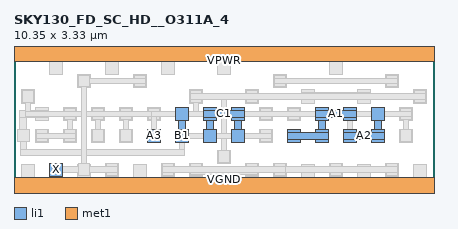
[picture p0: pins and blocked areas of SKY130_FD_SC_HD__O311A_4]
MACRO SKY130_FD_SC_HD__O311A_4
 CLASS CORE ;
 FOREIGN SKY130_FD_SC_HD__O311A_4 0 0 ;
 SIZE 10.35 BY 3.33 ;
 ORIGIN 0 0 ;
 SYMMETRY X Y R90 ;
 SITE unit ;
  PIN VPWR
   DIRECTION INOUT ;
   USE POWER ;
   SHAPE ABUTMENT ;
    PORT
     CLASS CORE ;
       LAYER li1 ;
        RECT 0.00000000 3.09000000 10.35000000 3.57000000 ;
       LAYER met1 ;
        RECT 0.00000000 3.09000000 10.35000000 3.57000000 ;
    END
  END VPWR

  PIN VGND
   DIRECTION INOUT ;
   USE POWER ;
   SHAPE ABUTMENT ;
    PORT
     CLASS CORE ;
       LAYER li1 ;
        RECT 0.00000000 -0.24000000 10.35000000 0.24000000 ;
       LAYER met1 ;
        RECT 0.00000000 -0.24000000 10.35000000 0.24000000 ;
    END
  END VGND

  PIN X
   DIRECTION INOUT ;
   USE SIGNAL ;
   SHAPE ABUTMENT ;
    PORT
     CLASS CORE ;
       LAYER li1 ;
        RECT 0.87000000 0.26000000 1.20000000 0.59000000 ;
    END
  END X

  PIN B1
   DIRECTION INOUT ;
   USE SIGNAL ;
   SHAPE ABUTMENT ;
    PORT
     CLASS CORE ;
       LAYER li1 ;
        RECT 3.97500000 1.09500000 4.30500000 1.42500000 ;
        RECT 4.05500000 1.42500000 4.22500000 1.63500000 ;
        RECT 3.97500000 1.63500000 4.30500000 1.96500000 ;
    END
  END B1

  PIN A3
   DIRECTION INOUT ;
   USE SIGNAL ;
   SHAPE ABUTMENT ;
    PORT
     CLASS CORE ;
       LAYER li1 ;
        RECT 3.28500000 1.09500000 3.61500000 1.42500000 ;
    END
  END A3

  PIN A1
   DIRECTION INOUT ;
   USE SIGNAL ;
   SHAPE ABUTMENT ;
    PORT
     CLASS CORE ;
       LAYER li1 ;
        RECT 6.73500000 1.09500000 7.06500000 1.17500000 ;
        RECT 7.42500000 1.09500000 7.75500000 1.17500000 ;
        RECT 6.73500000 1.17500000 7.75500000 1.34500000 ;
        RECT 6.73500000 1.34500000 7.06500000 1.42500000 ;
        RECT 7.42500000 1.34500000 7.75500000 1.42500000 ;
        RECT 7.50500000 1.42500000 7.67500000 1.63500000 ;
        RECT 7.42500000 1.63500000 7.75500000 1.71500000 ;
        RECT 8.11500000 1.63500000 8.44500000 1.71500000 ;
        RECT 7.42500000 1.71500000 8.44500000 1.88500000 ;
        RECT 7.42500000 1.88500000 7.75500000 1.96500000 ;
        RECT 8.11500000 1.88500000 8.44500000 1.96500000 ;
    END
  END A1

  PIN A2
   DIRECTION INOUT ;
   USE SIGNAL ;
   SHAPE ABUTMENT ;
    PORT
     CLASS CORE ;
       LAYER li1 ;
        RECT 8.11500000 1.09500000 8.44500000 1.17500000 ;
        RECT 8.80500000 1.09500000 9.13500000 1.17500000 ;
        RECT 8.11500000 1.17500000 9.13500000 1.34500000 ;
        RECT 8.11500000 1.34500000 8.44500000 1.42500000 ;
        RECT 8.80500000 1.34500000 9.13500000 1.42500000 ;
        RECT 8.88500000 1.42500000 9.05500000 1.63500000 ;
        RECT 8.80500000 1.63500000 9.13500000 1.96500000 ;
    END
  END A2

  PIN C1
   DIRECTION INOUT ;
   USE SIGNAL ;
   SHAPE ABUTMENT ;
    PORT
     CLASS CORE ;
       LAYER li1 ;
        RECT 4.66500000 1.09500000 4.99500000 1.42500000 ;
        RECT 5.35500000 1.09500000 5.68500000 1.42500000 ;
        RECT 4.74500000 1.42500000 4.91500000 1.63500000 ;
        RECT 5.43500000 1.42500000 5.60500000 1.63500000 ;
        RECT 4.66500000 1.63500000 4.99500000 1.71500000 ;
        RECT 5.35500000 1.63500000 5.68500000 1.71500000 ;
        RECT 4.66500000 1.71500000 5.68500000 1.88500000 ;
        RECT 4.66500000 1.88500000 4.99500000 1.96500000 ;
        RECT 5.35500000 1.88500000 5.68500000 1.96500000 ;
    END
  END C1

 OBS
    LAYER polycont ;
     RECT 0.60500000 1.17500000 0.77500000 1.34500000 ;
     RECT 1.29500000 1.17500000 1.46500000 1.34500000 ;
     RECT 1.98500000 1.17500000 2.15500000 1.34500000 ;
     RECT 2.67500000 1.17500000 2.84500000 1.34500000 ;
     RECT 1.29500000 1.71500000 1.46500000 1.88500000 ;
     RECT 1.98500000 1.71500000 2.15500000 1.88500000 ;
     RECT 2.67500000 1.71500000 2.84500000 1.88500000 ;
     RECT 3.36500000 1.71500000 3.53500000 1.88500000 ;
     RECT 8.19500000 1.17500000 8.36500000 1.34500000 ;
     RECT 8.88500000 1.17500000 9.05500000 1.34500000 ;
     RECT 6.81500000 1.71500000 6.98500000 1.88500000 ;
     RECT 8.88500000 1.71500000 9.05500000 1.88500000 ;
     RECT 6.81500000 1.17500000 6.98500000 1.34500000 ;
     RECT 7.50500000 1.17500000 7.67500000 1.34500000 ;
     RECT 7.50500000 1.71500000 7.67500000 1.88500000 ;
     RECT 8.19500000 1.71500000 8.36500000 1.88500000 ;
     RECT 3.36500000 1.17500000 3.53500000 1.34500000 ;
     RECT 9.57500000 1.17500000 9.74500000 1.34500000 ;
     RECT 6.12500000 1.71500000 6.29500000 1.88500000 ;
     RECT 9.57500000 1.71500000 9.74500000 1.88500000 ;
     RECT 4.74500000 1.17500000 4.91500000 1.34500000 ;
     RECT 5.43500000 1.17500000 5.60500000 1.34500000 ;
     RECT 4.74500000 1.71500000 4.91500000 1.88500000 ;
     RECT 5.43500000 1.71500000 5.60500000 1.88500000 ;
     RECT 4.05500000 1.17500000 4.22500000 1.34500000 ;
     RECT 6.12500000 1.17500000 6.29500000 1.34500000 ;
     RECT 0.60500000 1.71500000 0.77500000 1.88500000 ;
     RECT 4.05500000 1.71500000 4.22500000 1.88500000 ;

    LAYER pdiffc ;
     RECT 0.26000000 2.15000000 0.43000000 2.32000000 ;
     RECT 4.40000000 2.15000000 4.57000000 2.32000000 ;
     RECT 5.78000000 2.15000000 5.95000000 2.32000000 ;
     RECT 9.92000000 2.15000000 10.09000000 2.32000000 ;
     RECT 0.95000000 2.86000000 1.12000000 3.03000000 ;
     RECT 2.33000000 2.86000000 2.50000000 3.03000000 ;
     RECT 3.71000000 2.86000000 3.88000000 3.03000000 ;
     RECT 5.09000000 2.86000000 5.26000000 3.03000000 ;
     RECT 7.85000000 2.86000000 8.02000000 3.03000000 ;
     RECT 7.16000000 2.15000000 7.33000000 2.32000000 ;
     RECT 8.54000000 2.15000000 8.71000000 2.32000000 ;
     RECT 1.64000000 2.52500000 1.81000000 2.69500000 ;
     RECT 3.02000000 2.52500000 3.19000000 2.69500000 ;
     RECT 6.47000000 2.52500000 6.64000000 2.69500000 ;
     RECT 9.23000000 2.52500000 9.40000000 2.69500000 ;

    LAYER ndiffc ;
     RECT 5.09000000 0.66000000 5.26000000 0.83000000 ;
     RECT 4.40000000 0.34000000 4.57000000 0.51000000 ;
     RECT 5.78000000 0.34000000 5.95000000 0.51000000 ;
     RECT 3.71000000 0.34000000 3.88000000 0.51000000 ;
     RECT 6.47000000 0.34000000 6.64000000 0.51000000 ;
     RECT 7.85000000 0.34000000 8.02000000 0.51000000 ;
     RECT 9.23000000 0.34000000 9.40000000 0.51000000 ;
     RECT 0.26000000 0.30000000 0.43000000 0.47000000 ;
     RECT 1.64000000 0.30000000 1.81000000 0.47000000 ;
     RECT 3.02000000 0.30000000 3.19000000 0.47000000 ;
     RECT 7.16000000 0.30000000 7.33000000 0.47000000 ;
     RECT 8.54000000 0.30000000 8.71000000 0.47000000 ;
     RECT 9.92000000 0.30000000 10.09000000 0.47000000 ;
     RECT 0.95000000 0.34000000 1.12000000 0.51000000 ;
     RECT 2.33000000 0.34000000 2.50000000 0.51000000 ;

    LAYER li1 ;
     RECT 5.01000000 0.58000000 5.34000000 0.91000000 ;
     RECT 0.52500000 1.09500000 0.85500000 1.42500000 ;
     RECT 1.21500000 1.09500000 1.54500000 1.42500000 ;
     RECT 1.90500000 1.09500000 2.23500000 1.42500000 ;
     RECT 2.59500000 1.09500000 2.92500000 1.42500000 ;
     RECT 1.21500000 1.63500000 1.54500000 1.96500000 ;
     RECT 1.90500000 1.63500000 2.23500000 1.96500000 ;
     RECT 2.59500000 1.63500000 2.92500000 1.96500000 ;
     RECT 3.28500000 1.63500000 3.61500000 1.96500000 ;
     RECT 0.18000000 2.07000000 0.51000000 2.40000000 ;
     RECT 4.32000000 2.07000000 4.65000000 2.40000000 ;
     RECT 5.70000000 2.07000000 6.03000000 2.40000000 ;
     RECT 9.84000000 2.07000000 10.17000000 2.40000000 ;
     RECT 6.73500000 1.63500000 7.06500000 1.96500000 ;
     RECT 8.11500000 1.09500000 8.44500000 1.17500000 ;
     RECT 8.80500000 1.09500000 9.13500000 1.17500000 ;
     RECT 8.11500000 1.17500000 9.13500000 1.34500000 ;
     RECT 8.11500000 1.34500000 8.44500000 1.42500000 ;
     RECT 8.80500000 1.34500000 9.13500000 1.42500000 ;
     RECT 8.88500000 1.42500000 9.05500000 1.63500000 ;
     RECT 8.80500000 1.63500000 9.13500000 1.96500000 ;
     RECT 0.87000000 2.78000000 1.20000000 3.09000000 ;
     RECT 2.25000000 2.78000000 2.58000000 3.09000000 ;
     RECT 3.63000000 2.78000000 3.96000000 3.09000000 ;
     RECT 5.01000000 2.78000000 5.34000000 3.09000000 ;
     RECT 7.77000000 2.78000000 8.10000000 3.09000000 ;
     RECT 0.00000000 3.09000000 10.35000000 3.57000000 ;
     RECT 6.73500000 1.09500000 7.06500000 1.17500000 ;
     RECT 7.42500000 1.09500000 7.75500000 1.17500000 ;
     RECT 6.73500000 1.17500000 7.75500000 1.34500000 ;
     RECT 6.73500000 1.34500000 7.06500000 1.42500000 ;
     RECT 7.42500000 1.34500000 7.75500000 1.42500000 ;
     RECT 7.50500000 1.42500000 7.67500000 1.63500000 ;
     RECT 7.42500000 1.63500000 7.75500000 1.71500000 ;
     RECT 8.11500000 1.63500000 8.44500000 1.71500000 ;
     RECT 7.42500000 1.71500000 8.44500000 1.88500000 ;
     RECT 7.42500000 1.88500000 7.75500000 1.96500000 ;
     RECT 8.11500000 1.88500000 8.44500000 1.96500000 ;
     RECT 7.08000000 2.07000000 7.41000000 2.15000000 ;
     RECT 8.46000000 2.07000000 8.79000000 2.15000000 ;
     RECT 7.08000000 2.15000000 8.79000000 2.32000000 ;
     RECT 7.08000000 2.32000000 7.41000000 2.40000000 ;
     RECT 8.46000000 2.32000000 8.79000000 2.40000000 ;
     RECT 4.32000000 0.26000000 4.65000000 0.59000000 ;
     RECT 5.70000000 0.26000000 6.03000000 0.59000000 ;
     RECT 3.63000000 0.26000000 3.96000000 0.59000000 ;
     RECT 6.39000000 0.26000000 6.72000000 0.59000000 ;
     RECT 7.77000000 0.26000000 8.10000000 0.59000000 ;
     RECT 9.15000000 0.26000000 9.48000000 0.59000000 ;
     RECT 0.00000000 -0.24000000 10.35000000 0.24000000 ;
     RECT 0.18000000 0.24000000 0.51000000 0.55000000 ;
     RECT 1.56000000 0.24000000 1.89000000 0.55000000 ;
     RECT 2.94000000 0.24000000 3.27000000 0.55000000 ;
     RECT 7.08000000 0.24000000 7.41000000 0.55000000 ;
     RECT 8.46000000 0.24000000 8.79000000 0.55000000 ;
     RECT 9.84000000 0.24000000 10.17000000 0.55000000 ;
     RECT 3.28500000 1.09500000 3.61500000 1.42500000 ;
     RECT 9.49500000 1.09500000 9.82500000 1.42500000 ;
     RECT 6.04500000 1.63500000 6.37500000 1.96500000 ;
     RECT 9.49500000 1.63500000 9.82500000 1.96500000 ;
     RECT 4.66500000 1.09500000 4.99500000 1.42500000 ;
     RECT 5.35500000 1.09500000 5.68500000 1.42500000 ;
     RECT 4.74500000 1.42500000 4.91500000 1.63500000 ;
     RECT 5.43500000 1.42500000 5.60500000 1.63500000 ;
     RECT 4.66500000 1.63500000 4.99500000 1.71500000 ;
     RECT 5.35500000 1.63500000 5.68500000 1.71500000 ;
     RECT 4.66500000 1.71500000 5.68500000 1.88500000 ;
     RECT 4.66500000 1.88500000 4.99500000 1.96500000 ;
     RECT 5.35500000 1.88500000 5.68500000 1.96500000 ;
     RECT 6.04500000 1.09500000 6.37500000 1.42500000 ;
     RECT 0.14500000 1.17500000 0.31500000 1.71500000 ;
     RECT 0.52500000 1.63500000 0.85500000 1.71500000 ;
     RECT 0.14500000 1.71500000 0.85500000 1.88500000 ;
     RECT 0.52500000 1.88500000 0.85500000 1.96500000 ;
     RECT 3.97500000 1.09500000 4.30500000 1.42500000 ;
     RECT 4.05500000 1.42500000 4.22500000 1.63500000 ;
     RECT 3.97500000 1.63500000 4.30500000 1.96500000 ;
     RECT 0.87000000 0.26000000 1.20000000 0.59000000 ;
     RECT 2.25000000 0.26000000 2.58000000 0.59000000 ;
     RECT 1.56000000 2.44500000 1.89000000 2.77500000 ;
     RECT 2.94000000 2.44500000 3.27000000 2.77500000 ;
     RECT 6.39000000 2.44500000 6.72000000 2.77500000 ;
     RECT 9.15000000 2.44500000 9.48000000 2.77500000 ;

    LAYER viali ;
     RECT 5.09000000 0.66000000 5.26000000 0.83000000 ;
     RECT 0.60500000 1.17500000 0.77500000 1.34500000 ;
     RECT 1.29500000 1.17500000 1.46500000 1.34500000 ;
     RECT 1.98500000 1.17500000 2.15500000 1.34500000 ;
     RECT 2.67500000 1.17500000 2.84500000 1.34500000 ;
     RECT 1.29500000 1.71500000 1.46500000 1.88500000 ;
     RECT 1.98500000 1.71500000 2.15500000 1.88500000 ;
     RECT 2.67500000 1.71500000 2.84500000 1.88500000 ;
     RECT 3.36500000 1.71500000 3.53500000 1.88500000 ;
     RECT 0.26000000 2.15000000 0.43000000 2.32000000 ;
     RECT 4.40000000 2.15000000 4.57000000 2.32000000 ;
     RECT 5.78000000 2.15000000 5.95000000 2.32000000 ;
     RECT 9.92000000 2.15000000 10.09000000 2.32000000 ;
     RECT 8.19500000 1.17500000 8.36500000 1.34500000 ;
     RECT 6.81500000 1.71500000 6.98500000 1.88500000 ;
     RECT 0.95000000 3.24500000 1.12000000 3.41500000 ;
     RECT 4.40000000 0.34000000 4.57000000 0.51000000 ;
     RECT 5.78000000 0.34000000 5.95000000 0.51000000 ;
     RECT 3.71000000 0.34000000 3.88000000 0.51000000 ;
     RECT 6.47000000 0.34000000 6.64000000 0.51000000 ;
     RECT 7.85000000 0.34000000 8.02000000 0.51000000 ;
     RECT 9.23000000 0.34000000 9.40000000 0.51000000 ;
     RECT 0.26000000 -0.08500000 0.43000000 0.08500000 ;
     RECT 3.36500000 1.17500000 3.53500000 1.34500000 ;
     RECT 9.57500000 1.17500000 9.74500000 1.34500000 ;
     RECT 6.12500000 1.71500000 6.29500000 1.88500000 ;
     RECT 9.57500000 1.71500000 9.74500000 1.88500000 ;
     RECT 0.14500000 1.17500000 0.31500000 1.34500000 ;
     RECT 4.05500000 1.17500000 4.22500000 1.34500000 ;
     RECT 6.12500000 1.17500000 6.29500000 1.34500000 ;
     RECT 0.95000000 0.34000000 1.12000000 0.51000000 ;
     RECT 2.33000000 0.34000000 2.50000000 0.51000000 ;
     RECT 1.64000000 2.52500000 1.81000000 2.69500000 ;
     RECT 3.02000000 2.52500000 3.19000000 2.69500000 ;
     RECT 6.47000000 2.52500000 6.64000000 2.69500000 ;
     RECT 9.23000000 2.52500000 9.40000000 2.69500000 ;

    LAYER met1 ;
     RECT 5.03000000 0.60000000 5.32000000 0.89000000 ;
     RECT 0.54500000 1.11500000 0.83500000 1.19000000 ;
     RECT 1.23500000 1.11500000 1.52500000 1.19000000 ;
     RECT 0.54500000 1.19000000 1.52500000 1.33000000 ;
     RECT 0.54500000 1.33000000 0.83500000 1.40500000 ;
     RECT 1.23500000 1.33000000 1.52500000 1.40500000 ;
     RECT 1.92500000 1.11500000 2.21500000 1.40500000 ;
     RECT 2.61500000 1.11500000 2.90500000 1.40500000 ;
     RECT 1.31000000 1.40500000 1.45000000 1.65500000 ;
     RECT 2.00000000 1.40500000 2.14000000 1.65500000 ;
     RECT 2.69000000 1.40500000 2.83000000 1.65500000 ;
     RECT 1.23500000 1.65500000 1.52500000 1.73000000 ;
     RECT 1.92500000 1.65500000 2.21500000 1.73000000 ;
     RECT 2.61500000 1.65500000 2.90500000 1.73000000 ;
     RECT 3.30500000 1.65500000 3.59500000 1.73000000 ;
     RECT 0.27500000 1.73000000 4.55500000 1.87000000 ;
     RECT 1.23500000 1.87000000 1.52500000 1.94500000 ;
     RECT 1.92500000 1.87000000 2.21500000 1.94500000 ;
     RECT 2.61500000 1.87000000 2.90500000 1.94500000 ;
     RECT 3.30500000 1.87000000 3.59500000 1.94500000 ;
     RECT 0.27500000 1.87000000 0.41500000 2.09000000 ;
     RECT 4.41500000 1.87000000 4.55500000 2.09000000 ;
     RECT 4.34000000 2.09000000 4.63000000 2.16500000 ;
     RECT 5.10500000 0.89000000 5.24500000 2.16500000 ;
     RECT 5.72000000 2.09000000 6.01000000 2.16500000 ;
     RECT 9.86000000 2.09000000 10.15000000 2.16500000 ;
     RECT 4.34000000 2.16500000 10.15000000 2.30500000 ;
     RECT 0.20000000 2.09000000 0.49000000 2.38000000 ;
     RECT 4.34000000 2.30500000 4.63000000 2.38000000 ;
     RECT 5.72000000 2.30500000 6.01000000 2.38000000 ;
     RECT 9.86000000 2.30500000 10.15000000 2.38000000 ;
     RECT 8.13500000 1.11500000 8.42500000 1.40500000 ;
     RECT 6.75500000 1.65500000 7.04500000 1.73000000 ;
     RECT 8.21000000 1.40500000 8.35000000 1.73000000 ;
     RECT 6.75500000 1.73000000 8.35000000 1.87000000 ;
     RECT 6.75500000 1.87000000 7.04500000 1.94500000 ;
     RECT 0.00000000 3.09000000 10.35000000 3.57000000 ;
     RECT 4.34000000 0.28000000 4.63000000 0.31500000 ;
     RECT 5.72000000 0.28000000 6.01000000 0.31500000 ;
     RECT 4.34000000 0.31500000 6.01000000 0.45500000 ;
     RECT 4.34000000 0.45500000 4.63000000 0.57000000 ;
     RECT 5.72000000 0.45500000 6.01000000 0.57000000 ;
     RECT 3.65000000 0.28000000 3.94000000 0.57000000 ;
     RECT 6.41000000 0.28000000 6.70000000 0.35500000 ;
     RECT 7.79000000 0.28000000 8.08000000 0.35500000 ;
     RECT 9.17000000 0.28000000 9.46000000 0.35500000 ;
     RECT 6.41000000 0.35500000 9.46000000 0.49500000 ;
     RECT 6.41000000 0.49500000 6.70000000 0.57000000 ;
     RECT 7.79000000 0.49500000 8.08000000 0.57000000 ;
     RECT 9.17000000 0.49500000 9.46000000 0.57000000 ;
     RECT 0.00000000 -0.24000000 10.35000000 0.24000000 ;
     RECT 3.30500000 1.11500000 3.59500000 1.40500000 ;
     RECT 6.06500000 1.65500000 6.35500000 1.94500000 ;
     RECT 9.51500000 1.11500000 9.80500000 1.40500000 ;
     RECT 9.59000000 1.40500000 9.73000000 1.65500000 ;
     RECT 9.51500000 1.65500000 9.80500000 1.94500000 ;
     RECT 0.16000000 0.78500000 4.21000000 0.92500000 ;
     RECT 0.16000000 0.92500000 0.30000000 1.11500000 ;
     RECT 4.07000000 0.92500000 4.21000000 1.11500000 ;
     RECT 0.08500000 1.11500000 0.37500000 1.40500000 ;
     RECT 3.99500000 1.11500000 4.28500000 1.40500000 ;
     RECT 6.06500000 1.11500000 6.35500000 1.40500000 ;
     RECT 0.89000000 0.28000000 1.18000000 0.35500000 ;
     RECT 1.58000000 0.28000000 1.87000000 0.35500000 ;
     RECT 2.27000000 0.28000000 2.56000000 0.35500000 ;
     RECT 0.89000000 0.35500000 2.56000000 0.49500000 ;
     RECT 0.89000000 0.49500000 1.18000000 0.57000000 ;
     RECT 1.58000000 0.49500000 1.87000000 0.57000000 ;
     RECT 2.27000000 0.49500000 2.56000000 0.57000000 ;
     RECT 1.58000000 2.46500000 1.87000000 2.54000000 ;
     RECT 2.96000000 2.46500000 3.25000000 2.54000000 ;
     RECT 1.58000000 2.54000000 3.25000000 2.68000000 ;
     RECT 1.58000000 2.68000000 1.87000000 2.75500000 ;
     RECT 2.96000000 2.68000000 3.25000000 2.75500000 ;
     RECT 6.41000000 2.46500000 6.70000000 2.54000000 ;
     RECT 9.17000000 2.46500000 9.46000000 2.54000000 ;
     RECT 6.41000000 2.54000000 9.46000000 2.68000000 ;
     RECT 6.41000000 2.68000000 6.70000000 2.75500000 ;
     RECT 9.17000000 2.68000000 9.46000000 2.75500000 ;

    LAYER via ;
     RECT 3.71000000 0.34000000 3.88000000 0.51000000 ;
     RECT 6.47000000 0.34000000 6.64000000 0.51000000 ;
     RECT 3.36500000 1.17500000 3.53500000 1.34500000 ;
     RECT 6.12500000 1.71500000 6.29500000 1.88500000 ;
     RECT 9.57500000 1.71500000 9.74500000 1.88500000 ;
     RECT 4.05500000 1.17500000 4.22500000 1.34500000 ;
     RECT 6.12500000 1.17500000 6.29500000 1.34500000 ;
     RECT 1.64000000 0.34000000 1.81000000 0.51000000 ;
     RECT 1.64000000 2.52500000 1.81000000 2.69500000 ;

    LAYER met2 ;
     RECT 3.65000000 0.28000000 3.94000000 0.35500000 ;
     RECT 6.41000000 0.28000000 6.70000000 0.35500000 ;
     RECT 3.65000000 0.35500000 6.70000000 0.49500000 ;
     RECT 3.65000000 0.49500000 3.94000000 0.57000000 ;
     RECT 6.41000000 0.49500000 6.70000000 0.57000000 ;
     RECT 3.30500000 1.11500000 3.59500000 1.40500000 ;
     RECT 3.38000000 1.40500000 3.52000000 1.73000000 ;
     RECT 6.06500000 1.65500000 6.35500000 1.73000000 ;
     RECT 9.51500000 1.65500000 9.80500000 1.73000000 ;
     RECT 3.38000000 1.73000000 9.80500000 1.87000000 ;
     RECT 6.06500000 1.87000000 6.35500000 1.94500000 ;
     RECT 9.51500000 1.87000000 9.80500000 1.94500000 ;
     RECT 3.99500000 1.11500000 4.28500000 1.19000000 ;
     RECT 6.06500000 1.11500000 6.35500000 1.19000000 ;
     RECT 3.99500000 1.19000000 6.35500000 1.33000000 ;
     RECT 3.99500000 1.33000000 4.28500000 1.40500000 ;
     RECT 6.06500000 1.33000000 6.35500000 1.40500000 ;
     RECT 1.58000000 0.28000000 1.87000000 0.57000000 ;
     RECT 1.65500000 0.57000000 1.79500000 2.46500000 ;
     RECT 1.58000000 2.46500000 1.87000000 2.75500000 ;

    LAYER via2 ;


    LAYER met3 ;


 END
END SKY130_FD_SC_HD__O311A_4
